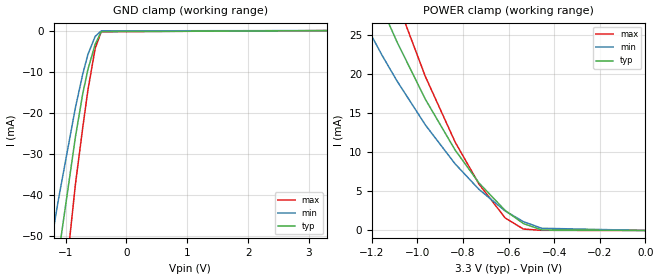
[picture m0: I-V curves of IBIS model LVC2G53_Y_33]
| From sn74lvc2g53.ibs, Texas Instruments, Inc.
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[Model]   LVC2G53_Y_33
Model_type  Terminator
| variable   typ   min   max
C_comp   6.91pF   6.21pF   7.61pF
| C_tri-state   6.91pF   6.21pF   7.61pF
[Temperature Range]   40   100   -40
| Ambient temperature   25   85   -40
[Voltage range]   3.3   3   3.6
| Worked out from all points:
|   GND clamp passes 1 mA (typ) near -0.45 V on its own axis
|   POWER clamp passes 1 mA (typ) near -0.54 V on its own axis
[GND Clamp]
| LVC2G53_Y_33
|   Voltage   I(typ)   I(min)   I(max)
-5.5V     -656.6mA   -514.9mA   -884.2mA
-1.51V    -100.3mA   -76.77mA   -137.9mA
-1.345V   -80.47mA   -61.22mA   -111.2mA
-1.29V    -74.02mA   -56.17mA   -102.5mA
-1.14V    -56.95mA   -42.83mA   -79.51mA
-1.115V   -54.18mA   -40.67mA   -75.77mA
-840mV    -25.85mA   -18.72mA   -37.35mA
-720mV    -15.38mA   -10.61mA   -23.64mA
-635mV    -9.476mA   -5.823mA   -14.52mA
-515mV    -3.302mA   -1.409mA   -4.34mA
-415mV    -257.2uA   -60.28uA   -263.3uA
3.3V      451.3pA    6.233uA    3.589nA
[POWER Clamp]
| LVC2G53_Y_33
|   Voltage   I(typ)   I(min)   I(max)
-5.5V     646.3mA    509.2mA    851.3mA
-1.285V   37.65mA    29.47mA    47.18mA
-1.255V   35.41mA    27.76mA    44.21mA
-1.155V   28.34mA    22.35mA    34.86mA
-1.09V    24.09mA    19.1mA     29.27mA
-965mV    16.73mA    13.46mA    19.63mA
-835mV    10.28mA    8.509mA    11.3mA
-730mV    6.059mA    5.242mA    5.92mA
-615mV    2.544mA    2.484mA    1.591mA
-535mV    877.3uA    1.122mA    179.7uA
-455mV    67.18uA    283uA      17.81uA
-95.1fV   451.3pA    2.86nA     10.07nA
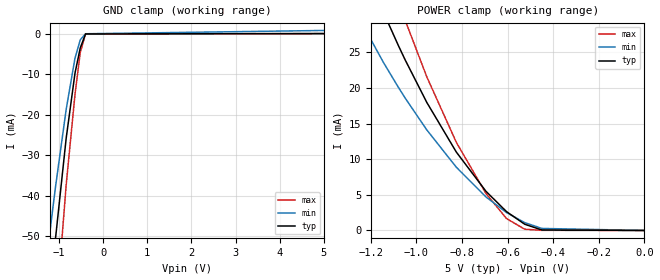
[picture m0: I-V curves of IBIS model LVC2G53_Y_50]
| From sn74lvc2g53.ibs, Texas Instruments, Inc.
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[Model]   LVC2G53_Y_50
Model_type  Terminator
| variable   typ   min   max
C_comp   7.09pF   5.95pF   10.73pF
| C_tri-state   7.09pF   5.95pF   10.73pF
[Temperature Range]   40   100   -40
| Ambient temperature   25   85   -40
[Voltage range]   5   4.5   5.5
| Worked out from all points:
|   GND clamp passes 1 mA (typ) near -0.45 V on its own axis
|   POWER clamp passes 1 mA (typ) near -0.53 V on its own axis
[GND Clamp]
| LVC2G53_Y_50
|   Voltage   I(typ)   I(min)   I(max)
-5.5V     -656.6mA   -514.9mA   -884.2mA
-1.505V   -99.68mA   -76.29mA   -137mA
-1.445V   -92.4mA    -70.58mA   -127.3mA
-1.335V   -79.29mA   -60.3mA    -109.6mA
-1.28V    -72.86mA   -55.26mA   -101mA
-1.125V   -55.29mA   -41.53mA   -77.26mA
-1.08V    -50.35mA   -37.69mA   -70.6mA
-840mV    -25.85mA   -18.72mA   -37.35mA
-640mV    -9.779mA   -6.074mA   -15.04mA
-520mV    -3.519mA   -1.53mA    -4.658mA
-400mV    -91.99uA   -42.2uA    -76.79uA
5V        533.3pA    768.8uA    4.041nA
[POWER Clamp]
| LVC2G53_Y_50
|   Voltage   I(typ)   I(min)   I(max)
-5.5V     702.8mA    542.7mA    943.4mA
-1.275V   40.73mA    31.14mA    52.12mA
-1.145V   30.6mA     23.57mA    38.45mA
-1.08V    25.98mA    20.11mA    32.24mA
-1.05V    23.95mA    18.59mA    29.52mA
-955mV    17.98mA    14.12mA    21.57mA
-825mV    10.99mA    8.866mA    12.35mA
-695mV    5.493mA    4.702mA    5.191mA
-605mV    2.645mA    2.516mA    1.672mA
-525mV    872.1uA    1.1mA      175.6uA
-450mV    71.44uA    284.7uA    18.79uA
-95.1fV   533.3pA    3.123nA    11.59nA
